VERSION 5.8 ;
BUSBITCHARS "[]" ;
DIVIDERCHAR "/" ;
UNITS
    DATABASE MICRONS 1000 ;
END UNITS

VIA PLL_RING_DCO_PHYS_via1_2_1000_160_1_5_200_200
  VIARULE MET2_MET1 ;
  CUTSIZE 0.09 0.09 ;
  LAYERS MET1 VIA1 MET2 ;
  CUTSPACING 0.11 0.11 ;
  ENCLOSURE 0.04 0.035 0.04 0.005 ;
  ROWCOL 1 5 ;
END PLL_RING_DCO_PHYS_via1_2_1000_160_1_5_200_200

VIA PLL_RING_DCO_PHYS_via2_3_1000_160_1_5_200_200
  VIARULE MET3_MET2 ;
  CUTSIZE 0.09 0.09 ;
  LAYERS MET2 VIA2 MET3 ;
  CUTSPACING 0.11 0.11 ;
  ENCLOSURE 0.04 0.005 0.04 0.005 ;
  ROWCOL 1 5 ;
END PLL_RING_DCO_PHYS_via2_3_1000_160_1_5_200_200

VIA PLL_RING_DCO_PHYS_via3_4_1000_160_1_5_200_200
  VIARULE MET4_MET3 ;
  CUTSIZE 0.09 0.09 ;
  LAYERS MET3 VIA3 MET4 ;
  CUTSPACING 0.11 0.11 ;
  ENCLOSURE 0.04 0.005 0.055 0.04 ;
  ROWCOL 1 5 ;
END PLL_RING_DCO_PHYS_via3_4_1000_160_1_5_200_200

VIA PLL_RING_DCO_PHYS_via4_5_3100_3100_15_15_200_200
  VIARULE MET5_MET4 ;
  CUTSIZE 0.09 0.09 ;
  LAYERS MET4 VIA4 MET5 ;
  CUTSPACING 0.11 0.11 ;
  ENCLOSURE 0.105 0.02 0.04 0.105 ;
  ROWCOL 15 15 ;
END PLL_RING_DCO_PHYS_via4_5_3100_3100_15_15_200_200

VIA PLL_RING_DCO_PHYS_via4_5_3100_1000_5_15_200_200
  VIARULE MET5_MET4 ;
  CUTSIZE 0.09 0.09 ;
  LAYERS MET4 VIA4 MET5 ;
  CUTSPACING 0.11 0.11 ;
  ENCLOSURE 0.105 0.02 0.04 0.055 ;
  ROWCOL 5 15 ;
END PLL_RING_DCO_PHYS_via4_5_3100_1000_5_15_200_200

VIA PLL_RING_DCO_PHYS_via4_5_1000_3100_15_5_200_200
  VIARULE MET5_MET4 ;
  CUTSIZE 0.09 0.09 ;
  LAYERS MET4 VIA4 MET5 ;
  CUTSPACING 0.11 0.11 ;
  ENCLOSURE 0.055 0.02 0.04 0.105 ;
  ROWCOL 15 5 ;
END PLL_RING_DCO_PHYS_via4_5_1000_3100_15_5_200_200

VIA PLL_RING_DCO_PHYS_via4_5_1000_1000_5_5_200_200
  VIARULE MET5_MET4 ;
  CUTSIZE 0.09 0.09 ;
  LAYERS MET4 VIA4 MET5 ;
  CUTSPACING 0.11 0.11 ;
  ENCLOSURE 0.055 0.02 0.04 0.055 ;
  ROWCOL 5 5 ;
END PLL_RING_DCO_PHYS_via4_5_1000_1000_5_5_200_200

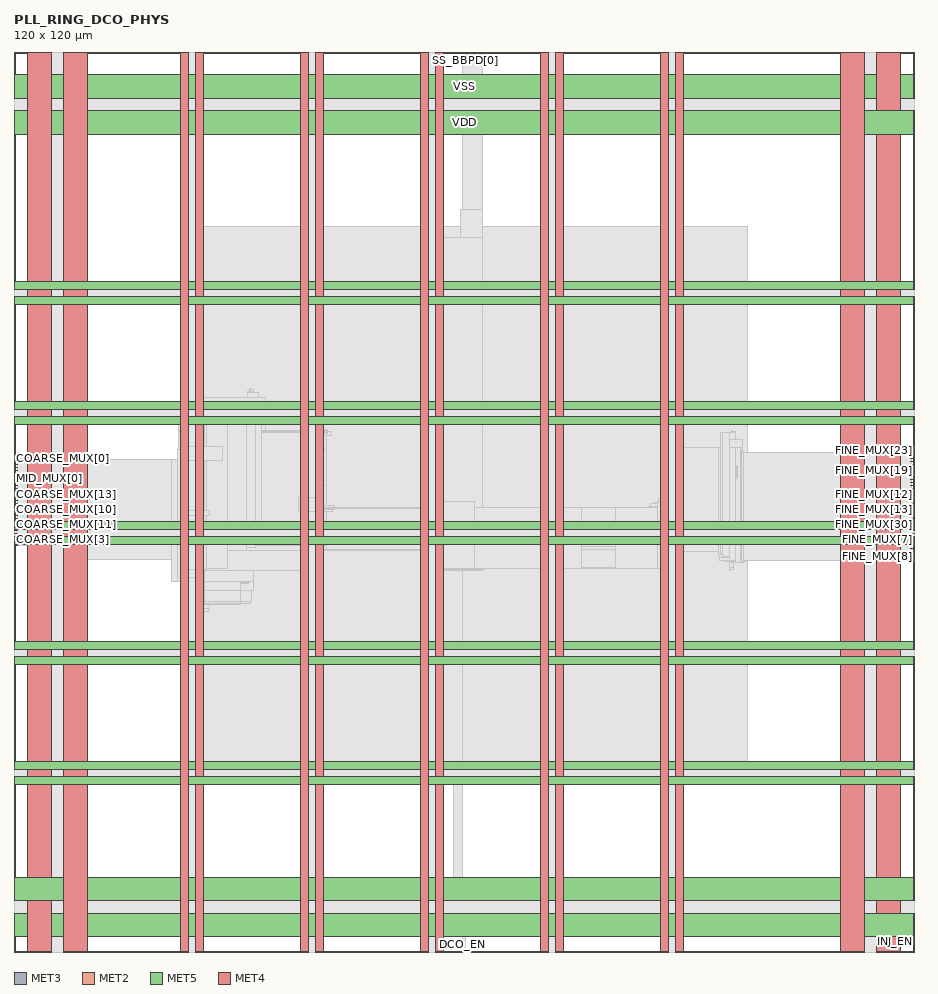
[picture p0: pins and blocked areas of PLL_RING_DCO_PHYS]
MACRO PLL_RING_DCO_PHYS
  FOREIGN PLL_RING_DCO_PHYS 0 0 ;
  CLASS BLOCK ;
  SIZE 120 BY 120 ;
  PIN COARSE_MUX[0]
    DIRECTION INPUT ;
    USE SIGNAL ;
    PORT
      LAYER MET3 ;
        RECT  0 65.75 0.52 65.85 ;
    END
  END COARSE_MUX[0]
  PIN COARSE_MUX[10]
    DIRECTION INPUT ;
    USE SIGNAL ;
    PORT
      LAYER MET3 ;
        RECT  0 58.95 0.52 59.05 ;
    END
  END COARSE_MUX[10]
  PIN COARSE_MUX[11]
    DIRECTION INPUT ;
    USE SIGNAL ;
    PORT
      LAYER MET3 ;
        RECT  0 56.95 0.52 57.05 ;
    END
  END COARSE_MUX[11]
  PIN COARSE_MUX[12]
    DIRECTION INPUT ;
    USE SIGNAL ;
    PORT
      LAYER MET3 ;
        RECT  0 60.55 0.52 60.65 ;
    END
  END COARSE_MUX[12]
  PIN COARSE_MUX[13]
    DIRECTION INPUT ;
    USE SIGNAL ;
    PORT
      LAYER MET3 ;
        RECT  0 60.95 0.52 61.05 ;
    END
  END COARSE_MUX[13]
  PIN COARSE_MUX[14]
    DIRECTION INPUT ;
    USE SIGNAL ;
    PORT
      LAYER MET3 ;
        RECT  0 56.55 0.52 56.65 ;
    END
  END COARSE_MUX[14]
  PIN COARSE_MUX[1]
    DIRECTION INPUT ;
    USE SIGNAL ;
    PORT
      LAYER MET3 ;
        RECT  0 59.35 0.52 59.45 ;
    END
  END COARSE_MUX[1]
  PIN COARSE_MUX[2]
    DIRECTION INPUT ;
    USE SIGNAL ;
    PORT
      LAYER MET3 ;
        RECT  0 61.75 0.52 61.85 ;
    END
  END COARSE_MUX[2]
  PIN COARSE_MUX[3]
    DIRECTION INPUT ;
    USE SIGNAL ;
    PORT
      LAYER MET3 ;
        RECT  0 54.95 0.52 55.05 ;
    END
  END COARSE_MUX[3]
  PIN COARSE_MUX[4]
    DIRECTION INPUT ;
    USE SIGNAL ;
    PORT
      LAYER MET3 ;
        RECT  0 62.55 0.52 62.65 ;
    END
  END COARSE_MUX[4]
  PIN COARSE_MUX[5]
    DIRECTION INPUT ;
    USE SIGNAL ;
    PORT
      LAYER MET3 ;
        RECT  0 56.15 0.52 56.25 ;
    END
  END COARSE_MUX[5]
  PIN COARSE_MUX[6]
    DIRECTION INPUT ;
    USE SIGNAL ;
    PORT
      LAYER MET3 ;
        RECT  0 60.15 0.52 60.25 ;
    END
  END COARSE_MUX[6]
  PIN COARSE_MUX[7]
    DIRECTION INPUT ;
    USE SIGNAL ;
    PORT
      LAYER MET3 ;
        RECT  0 63.35 0.52 63.45 ;
    END
  END COARSE_MUX[7]
  PIN COARSE_MUX[8]
    DIRECTION INPUT ;
    USE SIGNAL ;
    PORT
      LAYER MET3 ;
        RECT  0 57.75 0.52 57.85 ;
    END
  END COARSE_MUX[8]
  PIN COARSE_MUX[9]
    DIRECTION INPUT ;
    USE SIGNAL ;
    PORT
      LAYER MET3 ;
        RECT  0 58.55 0.52 58.65 ;
    END
  END COARSE_MUX[9]
  PIN DCO_EN
    DIRECTION INPUT ;
    USE SIGNAL ;
    PORT
      LAYER MET2 ;
        RECT  59.75 0 59.85 0.52 ;
    END
  END DCO_EN
  PIN FINE_MUX[0]
    DIRECTION INPUT ;
    USE SIGNAL ;
    PORT
      LAYER MET3 ;
        RECT  119.48 57.75 120 57.85 ;
    END
  END FINE_MUX[0]
  PIN FINE_MUX[10]
    DIRECTION INPUT ;
    USE SIGNAL ;
    PORT
      LAYER MET3 ;
        RECT  119.48 65.35 120 65.45 ;
    END
  END FINE_MUX[10]
  PIN FINE_MUX[11]
    DIRECTION INPUT ;
    USE SIGNAL ;
    PORT
      LAYER MET3 ;
        RECT  119.48 63.35 120 63.45 ;
    END
  END FINE_MUX[11]
  PIN FINE_MUX[12]
    DIRECTION INPUT ;
    USE SIGNAL ;
    PORT
      LAYER MET3 ;
        RECT  119.48 60.95 120 61.05 ;
    END
  END FINE_MUX[12]
  PIN FINE_MUX[13]
    DIRECTION INPUT ;
    USE SIGNAL ;
    PORT
      LAYER MET3 ;
        RECT  119.48 58.95 120 59.05 ;
    END
  END FINE_MUX[13]
  PIN FINE_MUX[14]
    DIRECTION INPUT ;
    USE SIGNAL ;
    PORT
      LAYER MET3 ;
        RECT  119.48 63.75 120 63.85 ;
    END
  END FINE_MUX[14]
  PIN FINE_MUX[15]
    DIRECTION INPUT ;
    USE SIGNAL ;
    PORT
      LAYER MET3 ;
        RECT  119.48 60.55 120 60.65 ;
    END
  END FINE_MUX[15]
  PIN FINE_MUX[16]
    DIRECTION INPUT ;
    USE SIGNAL ;
    PORT
      LAYER MET3 ;
        RECT  119.48 66.55 120 66.65 ;
    END
  END FINE_MUX[16]
  PIN FINE_MUX[17]
    DIRECTION INPUT ;
    USE SIGNAL ;
    PORT
      LAYER MET3 ;
        RECT  119.48 58.15 120 58.25 ;
    END
  END FINE_MUX[17]
  PIN FINE_MUX[18]
    DIRECTION INPUT ;
    USE SIGNAL ;
    PORT
      LAYER MET3 ;
        RECT  119.48 62.55 120 62.65 ;
    END
  END FINE_MUX[18]
  PIN FINE_MUX[19]
    DIRECTION INPUT ;
    USE SIGNAL ;
    PORT
      LAYER MET3 ;
        RECT  119.48 64.15 120 64.25 ;
    END
  END FINE_MUX[19]
  PIN FINE_MUX[1]
    DIRECTION INPUT ;
    USE SIGNAL ;
    PORT
      LAYER MET3 ;
        RECT  119.48 61.75 120 61.85 ;
    END
  END FINE_MUX[1]
  PIN FINE_MUX[20]
    DIRECTION INPUT ;
    USE SIGNAL ;
    PORT
      LAYER MET3 ;
        RECT  119.48 56.55 120 56.65 ;
    END
  END FINE_MUX[20]
  PIN FINE_MUX[21]
    DIRECTION INPUT ;
    USE SIGNAL ;
    PORT
      LAYER MET3 ;
        RECT  119.48 56.15 120 56.25 ;
    END
  END FINE_MUX[21]
  PIN FINE_MUX[22]
    DIRECTION INPUT ;
    USE SIGNAL ;
    PORT
      LAYER MET3 ;
        RECT  119.48 61.35 120 61.45 ;
    END
  END FINE_MUX[22]
  PIN FINE_MUX[23]
    DIRECTION INPUT ;
    USE SIGNAL ;
    PORT
      LAYER MET3 ;
        RECT  119.48 65.75 120 65.85 ;
    END
  END FINE_MUX[23]
  PIN FINE_MUX[24]
    DIRECTION INPUT ;
    USE SIGNAL ;
    PORT
      LAYER MET3 ;
        RECT  119.48 55.35 120 55.45 ;
    END
  END FINE_MUX[24]
  PIN FINE_MUX[25]
    DIRECTION INPUT ;
    USE SIGNAL ;
    PORT
      LAYER MET3 ;
        RECT  119.48 57.35 120 57.45 ;
    END
  END FINE_MUX[25]
  PIN FINE_MUX[26]
    DIRECTION INPUT ;
    USE SIGNAL ;
    PORT
      LAYER MET3 ;
        RECT  119.48 64.55 120 64.65 ;
    END
  END FINE_MUX[26]
  PIN FINE_MUX[27]
    DIRECTION INPUT ;
    USE SIGNAL ;
    PORT
      LAYER MET3 ;
        RECT  119.48 60.15 120 60.25 ;
    END
  END FINE_MUX[27]
  PIN FINE_MUX[28]
    DIRECTION INPUT ;
    USE SIGNAL ;
    PORT
      LAYER MET3 ;
        RECT  119.48 66.15 120 66.25 ;
    END
  END FINE_MUX[28]
  PIN FINE_MUX[29]
    DIRECTION INPUT ;
    USE SIGNAL ;
    PORT
      LAYER MET3 ;
        RECT  119.48 58.55 120 58.65 ;
    END
  END FINE_MUX[29]
  PIN FINE_MUX[2]
    DIRECTION INPUT ;
    USE SIGNAL ;
    PORT
      LAYER MET3 ;
        RECT  119.48 62.15 120 62.25 ;
    END
  END FINE_MUX[2]
  PIN FINE_MUX[30]
    DIRECTION INPUT ;
    USE SIGNAL ;
    PORT
      LAYER MET3 ;
        RECT  119.48 56.95 120 57.05 ;
    END
  END FINE_MUX[30]
  PIN FINE_MUX[3]
    DIRECTION INPUT ;
    USE SIGNAL ;
    PORT
      LAYER MET3 ;
        RECT  119.48 59.75 120 59.85 ;
    END
  END FINE_MUX[3]
  PIN FINE_MUX[4]
    DIRECTION INPUT ;
    USE SIGNAL ;
    PORT
      LAYER MET3 ;
        RECT  119.48 54.55 120 54.65 ;
    END
  END FINE_MUX[4]
  PIN FINE_MUX[5]
    DIRECTION INPUT ;
    USE SIGNAL ;
    PORT
      LAYER MET3 ;
        RECT  119.48 64.95 120 65.05 ;
    END
  END FINE_MUX[5]
  PIN FINE_MUX[6]
    DIRECTION INPUT ;
    USE SIGNAL ;
    PORT
      LAYER MET3 ;
        RECT  119.48 54.15 120 54.25 ;
    END
  END FINE_MUX[6]
  PIN FINE_MUX[7]
    DIRECTION INPUT ;
    USE SIGNAL ;
    PORT
      LAYER MET3 ;
        RECT  119.48 54.95 120 55.05 ;
    END
  END FINE_MUX[7]
  PIN FINE_MUX[8]
    DIRECTION INPUT ;
    USE SIGNAL ;
    PORT
      LAYER MET3 ;
        RECT  119.48 53.75 120 53.85 ;
    END
  END FINE_MUX[8]
  PIN FINE_MUX[9]
    DIRECTION INPUT ;
    USE SIGNAL ;
    PORT
      LAYER MET3 ;
        RECT  119.48 62.95 120 63.05 ;
    END
  END FINE_MUX[9]
  PIN INJ_EN
    DIRECTION INPUT ;
    USE SIGNAL ;
    PORT
      LAYER MET3 ;
        RECT  119.48 1.35 120 1.45 ;
    END
  END INJ_EN
  PIN MID_MUX[0]
    DIRECTION INPUT ;
    USE SIGNAL ;
    PORT
      LAYER MET3 ;
        RECT  0 64.15 0.52 64.25 ;
    END
  END MID_MUX[0]
  PIN MID_MUX[10]
    DIRECTION INPUT ;
    USE SIGNAL ;
    PORT
      LAYER MET3 ;
        RECT  0 64.55 0.52 64.65 ;
    END
  END MID_MUX[10]
  PIN MID_MUX[11]
    DIRECTION INPUT ;
    USE SIGNAL ;
    PORT
      LAYER MET3 ;
        RECT  0 55.75 0.52 55.85 ;
    END
  END MID_MUX[11]
  PIN MID_MUX[12]
    DIRECTION INPUT ;
    USE SIGNAL ;
    PORT
      LAYER MET3 ;
        RECT  0 58.15 0.52 58.25 ;
    END
  END MID_MUX[12]
  PIN MID_MUX[13]
    DIRECTION INPUT ;
    USE SIGNAL ;
    PORT
      LAYER MET3 ;
        RECT  0 61.35 0.52 61.45 ;
    END
  END MID_MUX[13]
  PIN MID_MUX[14]
    DIRECTION INPUT ;
    USE SIGNAL ;
    PORT
      LAYER MET3 ;
        RECT  0 64.95 0.52 65.05 ;
    END
  END MID_MUX[14]
  PIN MID_MUX[1]
    DIRECTION INPUT ;
    USE SIGNAL ;
    PORT
      LAYER MET3 ;
        RECT  0 57.35 0.52 57.45 ;
    END
  END MID_MUX[1]
  PIN MID_MUX[2]
    DIRECTION INPUT ;
    USE SIGNAL ;
    PORT
      LAYER MET3 ;
        RECT  0 54.55 0.52 54.65 ;
    END
  END MID_MUX[2]
  PIN MID_MUX[3]
    DIRECTION INPUT ;
    USE SIGNAL ;
    PORT
      LAYER MET3 ;
        RECT  0 65.35 0.52 65.45 ;
    END
  END MID_MUX[3]
  PIN MID_MUX[4]
    DIRECTION INPUT ;
    USE SIGNAL ;
    PORT
      LAYER MET3 ;
        RECT  0 62.15 0.52 62.25 ;
    END
  END MID_MUX[4]
  PIN MID_MUX[5]
    DIRECTION INPUT ;
    USE SIGNAL ;
    PORT
      LAYER MET3 ;
        RECT  0 62.95 0.52 63.05 ;
    END
  END MID_MUX[5]
  PIN MID_MUX[6]
    DIRECTION INPUT ;
    USE SIGNAL ;
    PORT
      LAYER MET3 ;
        RECT  0 55.35 0.52 55.45 ;
    END
  END MID_MUX[6]
  PIN MID_MUX[7]
    DIRECTION INPUT ;
    USE SIGNAL ;
    PORT
      LAYER MET3 ;
        RECT  0 63.75 0.52 63.85 ;
    END
  END MID_MUX[7]
  PIN MID_MUX[8]
    DIRECTION INPUT ;
    USE SIGNAL ;
    PORT
      LAYER MET3 ;
        RECT  0 54.15 0.52 54.25 ;
    END
  END MID_MUX[8]
  PIN MID_MUX[9]
    DIRECTION INPUT ;
    USE SIGNAL ;
    PORT
      LAYER MET3 ;
        RECT  0 59.75 0.52 59.85 ;
    END
  END MID_MUX[9]
  PIN MID_OUT
    DIRECTION OUTPUT ;
    USE SIGNAL ;
    PORT
      LAYER MET3 ;
        RECT  119.48 59.35 120 59.45 ;
    END
  END MID_OUT
  PIN OUT
    DIRECTION OUTPUT ;
    USE SIGNAL ;
    PORT
      LAYER MET3 ;
        RECT  119.48 53.35 120 53.45 ;
    END
  END OUT
  PIN INJ_EDGE
    DIRECTION OUTPUT ;
    USE SIGNAL ;
    PORT
      LAYER MET3 ;
        RECT  119.48 55.75 120 55.85 ;
    END
  END INJ_EDGE
  PIN REF
    DIRECTION INPUT ;
    USE SIGNAL ;
    PORT
      LAYER MET2 ;
        RECT  60.15 0 60.25 0.52 ;
    END
  END REF
  PIN SS_BBPD[0]
    DIRECTION OUTPUT ;
    USE SIGNAL ;
    PORT
      LAYER MET2 ;
        RECT  60.15 119.48 60.25 120 ;
    END
  END SS_BBPD[0]
  PIN SS_BBPD[1]
    DIRECTION OUTPUT ;
    USE SIGNAL ;
    PORT
      LAYER MET2 ;
        RECT  59.75 119.48 59.85 120 ;
    END
  END SS_BBPD[1]
  PIN VSS
    DIRECTION INOUT ;
    USE GROUND ;
    PORT
      LAYER MET5 ;
        RECT  119.9 88.4 120 89.4 ;
        RECT  0 88.4 0.1 89.4 ;
        RECT  0 88.4 120 89.4 ;
        RECT  119.9 72.4 120 73.4 ;
        RECT  0 72.4 0.1 73.4 ;
        RECT  0 72.4 120 73.4 ;
        RECT  119.9 56.4 120 57.4 ;
        RECT  0 56.4 0.1 57.4 ;
        RECT  0 56.4 120 57.4 ;
        RECT  119.9 40.4 120 41.4 ;
        RECT  0 40.4 0.1 41.4 ;
        RECT  0 40.4 120 41.4 ;
        RECT  119.9 24.4 120 25.4 ;
        RECT  0 24.4 0.1 25.4 ;
        RECT  0 24.4 120 25.4 ;
      LAYER MET4 ;
        RECT  88.2 119.9 89.2 120 ;
        RECT  88.2 0 89.2 0.1 ;
        RECT  88.2 0 89.2 120 ;
        RECT  72.2 119.9 73.2 120 ;
        RECT  72.2 0 73.2 0.1 ;
        RECT  72.2 0 73.2 120 ;
        RECT  56.2 119.9 57.2 120 ;
        RECT  56.2 0 57.2 0.1 ;
        RECT  56.2 0 57.2 120 ;
        RECT  40.2 119.9 41.2 120 ;
        RECT  40.2 0 41.2 0.1 ;
        RECT  40.2 0 41.2 120 ;
        RECT  24.2 119.9 25.2 120 ;
        RECT  24.2 0 25.2 0.1 ;
        RECT  24.2 0 25.2 120 ;
      LAYER MET5 ;
        RECT  119.9 113.85 120 116.95 ;
        RECT  0 113.85 0.1 116.95 ;
        RECT  0 113.85 120 116.95 ;
        RECT  119.9 2.05 120 5.15 ;
        RECT  0 2.05 0.1 5.15 ;
        RECT  0 2.05 120 5.15 ;
      LAYER MET4 ;
        RECT  115.05 119.9 118.15 120 ;
        RECT  115.05 0 118.15 0.1 ;
        RECT  115.05 0 118.15 120 ;
        RECT  1.85 119.9 4.95 120 ;
        RECT  1.85 0 4.95 0.1 ;
        RECT  1.85 0 4.95 120 ;
    END
  END VSS
  PIN VDD
    DIRECTION INOUT ;
    USE POWER ;
    PORT
      LAYER MET5 ;
        RECT  119.9 86.4 120 87.4 ;
        RECT  0 86.4 0.1 87.4 ;
        RECT  0 86.4 120 87.4 ;
        RECT  119.9 70.4 120 71.4 ;
        RECT  0 70.4 0.1 71.4 ;
        RECT  0 70.4 120 71.4 ;
        RECT  119.9 54.4 120 55.4 ;
        RECT  0 54.4 0.1 55.4 ;
        RECT  0 54.4 120 55.4 ;
        RECT  119.9 38.4 120 39.4 ;
        RECT  0 38.4 0.1 39.4 ;
        RECT  0 38.4 120 39.4 ;
        RECT  119.9 22.4 120 23.4 ;
        RECT  0 22.4 0.1 23.4 ;
        RECT  0 22.4 120 23.4 ;
      LAYER MET4 ;
        RECT  86.2 119.9 87.2 120 ;
        RECT  86.2 0 87.2 0.1 ;
        RECT  86.2 0 87.2 120 ;
        RECT  70.2 119.9 71.2 120 ;
        RECT  70.2 0 71.2 0.1 ;
        RECT  70.2 0 71.2 120 ;
        RECT  54.2 119.9 55.2 120 ;
        RECT  54.2 0 55.2 0.1 ;
        RECT  54.2 0 55.2 120 ;
        RECT  38.2 119.9 39.2 120 ;
        RECT  38.2 0 39.2 0.1 ;
        RECT  38.2 0 39.2 120 ;
        RECT  22.2 119.9 23.2 120 ;
        RECT  22.2 0 23.2 0.1 ;
        RECT  22.2 0 23.2 120 ;
      LAYER MET5 ;
        RECT  119.9 109.05 120 112.15 ;
        RECT  0 109.05 0.1 112.15 ;
        RECT  0 109.05 120 112.15 ;
        RECT  119.9 6.85 120 9.95 ;
        RECT  0 6.85 0.1 9.95 ;
        RECT  0 6.85 120 9.95 ;
      LAYER MET4 ;
        RECT  110.25 119.9 113.35 120 ;
        RECT  110.25 0 113.35 0.1 ;
        RECT  110.25 0 113.35 120 ;
        RECT  6.65 119.9 9.75 120 ;
        RECT  6.65 0 9.75 0.1 ;
        RECT  6.65 0 9.75 120 ;
    END
  END VDD
  OBS
    LAYER MET1 ;
     RECT  22.2 22.32 97.8 96.68 ;
    LAYER MET2 ;
     RECT  59.75 0.4 60.25 2.95 ;
     RECT  58.55 2.95 60.25 3.05 ;
     RECT  58.55 3.05 59.85 22.35 ;
     RECT  24.215 22.35 25.185 23.75 ;
     RECT  40.215 22.35 41.185 23.75 ;
     RECT  56.215 22.35 59.85 23.75 ;
     RECT  72.215 22.35 73.185 23.75 ;
     RECT  88.215 22.35 89.185 23.75 ;
     RECT  22.215 23.75 25.185 45.23 ;
     RECT  22.215 45.23 25.35 45.43 ;
     RECT  22.215 45.43 25.95 45.75 ;
     RECT  22.215 45.75 26.05 46.44 ;
     RECT  30.15 46.35 30.25 46.44 ;
     RECT  22.215 46.44 31.55 46.75 ;
     RECT  22.215 46.75 31.65 48.23 ;
     RECT  22.215 48.23 31.95 49.35 ;
     RECT  20.95 49.35 31.95 50.825 ;
     RECT  38.215 23.75 41.185 50.825 ;
     RECT  54.215 23.75 59.85 50.825 ;
     RECT  54.215 50.825 61.55 50.83 ;
     RECT  54.215 50.83 62.35 51.025 ;
     RECT  95.45 50.83 95.55 51.03 ;
     RECT  86.215 23.75 89.185 51.15 ;
     RECT  95.45 51.03 95.95 51.25 ;
     RECT  54.215 51.025 62.75 51.35 ;
     RECT  54.215 51.35 62.85 51.75 ;
     RECT  95.35 51.25 95.95 51.95 ;
     RECT  54.215 51.75 65.25 52.04 ;
     RECT  95.35 51.95 97.25 52.04 ;
     RECT  94.85 52.04 97.55 52.24 ;
     RECT  54.215 52.04 65.95 52.35 ;
     RECT  94.05 52.24 97.55 52.65 ;
     RECT  117.35 52.15 117.45 52.95 ;
     RECT  54.215 52.35 66.05 53.35 ;
     RECT  70.215 23.75 73.185 53.35 ;
     RECT  84.95 51.15 89.185 53.35 ;
     RECT  93.95 52.65 97.55 53.35 ;
     RECT  2.95 52.35 3.05 53.55 ;
     RECT  20.95 50.825 41.185 53.55 ;
     RECT  80.15 53.165 80.25 53.625 ;
     RECT  54.215 53.35 73.185 53.63 ;
     RECT  77.25 53.625 80.25 53.63 ;
     RECT  54.215 53.63 80.25 53.65 ;
     RECT  84.95 53.35 97.55 53.75 ;
     RECT  54.215 53.65 80.15 54.05 ;
     RECT  85.05 53.75 97.55 54.16 ;
     RECT  20.95 53.55 41.65 54.25 ;
     RECT  116.95 52.95 117.45 54.25 ;
     RECT  68.55 54.05 80.15 54.36 ;
     RECT  85.45 54.16 97.55 54.36 ;
     RECT  117.15 54.25 117.45 54.65 ;
     RECT  117.15 54.65 117.25 55.45 ;
     RECT  86.215 54.36 97.55 57.55 ;
     RECT  68.55 54.36 73.185 57.95 ;
     RECT  86.215 57.55 100.85 58.25 ;
     RECT  68.65 57.95 73.185 58.375 ;
     RECT  69.15 58.375 73.185 58.45 ;
     RECT  21.95 54.25 41.65 58.765 ;
     RECT  21.95 58.765 42.45 59.03 ;
     RECT  86.215 58.25 97.15 59.15 ;
     RECT  84.55 59.15 97.15 59.35 ;
     RECT  21.95 59.03 42.75 59.56 ;
     RECT  84.85 59.35 97.15 59.76 ;
     RECT  2.75 53.55 3.05 59.95 ;
     RECT  85.45 59.76 97.15 59.96 ;
     RECT  85.75 59.96 97.15 60.05 ;
     RECT  116.95 58.75 117.05 60.25 ;
     RECT  85.95 60.05 97.15 60.45 ;
     RECT  2.35 59.95 3.05 61.05 ;
     RECT  21.95 59.56 41.65 62.15 ;
     RECT  86.215 60.45 97.15 63.24 ;
     RECT  2.35 61.05 2.45 63.45 ;
     RECT  86.215 63.24 97.35 63.775 ;
     RECT  86.215 63.775 97.25 65.45 ;
     RECT  21.75 62.15 41.65 67.05 ;
     RECT  86.215 65.45 97.15 67.25 ;
     RECT  94.15 67.25 97.15 68.36 ;
     RECT  21.95 67.05 41.65 68.84 ;
     RECT  94.15 68.36 96.15 69.25 ;
     RECT  21.95 68.84 42.35 69.37 ;
     RECT  95.65 69.25 96.15 69.37 ;
     RECT  95.65 69.37 95.75 69.57 ;
     RECT  21.95 69.37 41.85 69.575 ;
     RECT  38.215 69.575 41.85 69.65 ;
     RECT  21.95 69.575 33.55 72.05 ;
     RECT  22.215 72.05 33.55 73.96 ;
     RECT  22.215 73.96 25.25 74.65 ;
     RECT  31.15 73.96 32.65 74.65 ;
     RECT  31.15 74.65 31.95 74.75 ;
     RECT  31.45 74.75 31.95 74.97 ;
     RECT  31.45 74.97 31.55 75.17 ;
     RECT  22.215 74.65 25.185 95.25 ;
     RECT  38.215 69.65 41.185 95.25 ;
     RECT  54.215 54.05 62.45 95.25 ;
     RECT  70.215 58.45 73.185 95.25 ;
     RECT  86.215 67.25 89.185 95.25 ;
     RECT  22.215 95.25 23.185 96.65 ;
     RECT  38.215 95.25 39.185 96.65 ;
     RECT  54.215 95.25 55.185 96.65 ;
     RECT  70.215 95.25 71.185 96.65 ;
     RECT  86.215 95.25 87.185 96.65 ;
     RECT  59.55 95.25 62.45 99.05 ;
     RECT  59.75 99.05 62.45 119.6 ;
     RECT  60.35 119.6 62.45 119.65 ;
    LAYER MET3 ;
     RECT  0.4 54.15 2.75 65.85 ;
     RECT  2.75 53.55 2.95 65.85 ;
     RECT  2.95 52.35 6.05 65.85 ;
     RECT  6.05 52.35 20.95 65.65 ;
     RECT  20.95 49.35 21.75 65.65 ;
     RECT  21.75 49.35 22.215 67.05 ;
     RECT  21.95 71.95 22.215 72.05 ;
     RECT  22.215 23.75 23.185 96.65 ;
     RECT  23.185 23.75 24.215 95.25 ;
     RECT  24.215 22.35 25.185 95.25 ;
     RECT  25.185 46.35 25.45 71.45 ;
     RECT  25.45 50.95 25.6 71.45 ;
     RECT  25.6 51.15 28.45 71.45 ;
     RECT  25.45 46.35 30.15 46.45 ;
     RECT  30.15 46.35 30.25 49.25 ;
     RECT  28.45 53.55 31.05 71.45 ;
     RECT  30.25 49.15 31.25 49.25 ;
     RECT  31.05 53.95 32.25 71.45 ;
     RECT  32.25 55.75 33.05 71.45 ;
     RECT  33.05 55.75 38.215 69.25 ;
     RECT  38.215 23.75 39.185 96.65 ;
     RECT  39.185 23.75 40.215 95.25 ;
     RECT  40.215 22.35 41.185 95.25 ;
     RECT  41.185 69.15 41.85 69.25 ;
     RECT  41.185 53.55 54.215 53.65 ;
     RECT  41.185 59.15 54.215 59.25 ;
     RECT  54.215 23.75 55.185 96.65 ;
     RECT  55.185 23.75 56.215 95.25 ;
     RECT  56.215 22.35 57.185 95.25 ;
     RECT  58.55 2.95 60.25 3.05 ;
     RECT  57.185 51.15 61.45 60.05 ;
     RECT  61.45 51.15 70.215 59.25 ;
     RECT  70.215 23.75 71.185 96.65 ;
     RECT  71.185 23.75 72.215 95.25 ;
     RECT  72.215 22.35 73.185 95.25 ;
     RECT  73.185 51.15 75.65 59.25 ;
     RECT  75.65 51.15 80.15 51.25 ;
     RECT  75.65 56.75 80.15 59.25 ;
     RECT  80.15 51.15 85.75 59.25 ;
     RECT  85.75 51.15 86.215 60.05 ;
     RECT  86.215 23.75 87.185 96.65 ;
     RECT  87.185 23.75 88.215 95.25 ;
     RECT  88.215 22.35 89.185 95.25 ;
     RECT  89.185 53.35 93.95 67.25 ;
     RECT  93.95 52.95 94.15 67.25 ;
     RECT  94.15 52.95 94.45 69.25 ;
     RECT  94.45 52.75 95.35 69.25 ;
     RECT  95.35 52.15 95.45 69.25 ;
     RECT  95.45 52.15 96.15 67.25 ;
     RECT  96.15 51.95 96.85 67.25 ;
     RECT  96.85 51.95 97.05 66.85 ;
     RECT  97.05 51.95 97.25 66.65 ;
     RECT  97.25 52.15 117.45 66.65 ;
     RECT  117.45 53.35 119.6 66.65 ;
    LAYER MET4 ;
     RECT  22.2 0 25.2 49.95 ;
     RECT  22.2 49.95 25.45 50.95 ;
     RECT  96.75 56.75 96.85 57.45 ;
     RECT  22.2 50.95 25.65 58.15 ;
     RECT  38.2 0 41.2 58.75 ;
     RECT  22.2 58.15 26.05 58.85 ;
     RECT  37.95 58.75 41.2 60.65 ;
     RECT  96.15 58.35 96.25 63.15 ;
     RECT  96.15 63.15 96.45 63.45 ;
     RECT  96.35 63.45 96.45 64.85 ;
     RECT  22.2 58.85 25.45 65.55 ;
     RECT  22.2 65.55 27.85 67.45 ;
     RECT  1.85 0 9.75 120 ;
     RECT  22.2 67.45 25.2 120 ;
     RECT  38.2 60.65 41.2 120 ;
     RECT  54.2 0 57.2 120 ;
     RECT  70.2 0 73.2 120 ;
     RECT  86.2 0 89.2 120 ;
     RECT  110.25 0 118.15 120 ;
    LAYER MET5 ;
     RECT  0 2.05 120 9.95 ;
     RECT  0 22.4 120 25.4 ;
     RECT  0 38.4 120 41.4 ;
     RECT  0 54.4 120 57.4 ;
     RECT  0 70.4 120 73.4 ;
     RECT  0 86.4 120 89.4 ;
     RECT  0 109.05 120 116.95 ;
  END
END PLL_RING_DCO_PHYS
END LIBRARY
